VERSION 5.7 ;
  NOWIREEXTENSIONATPIN ON ;
  DIVIDERCHAR "/" ;
  BUSBITCHARS "[]" ;
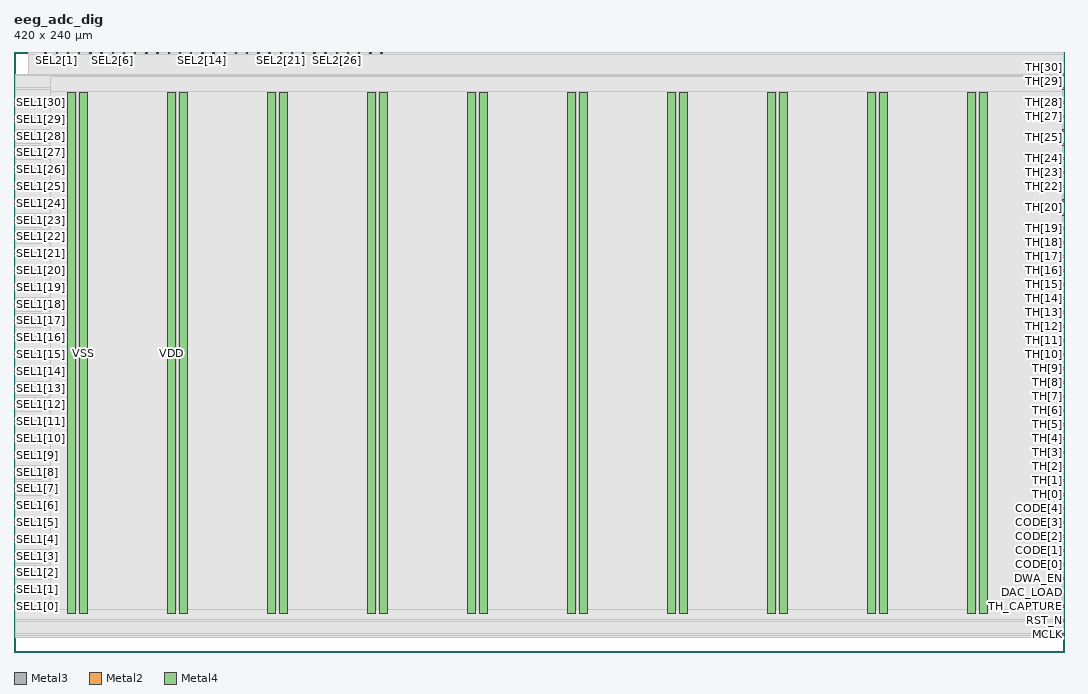
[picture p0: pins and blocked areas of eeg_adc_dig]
MACRO eeg_adc_dig
  CLASS BLOCK ;
  FOREIGN eeg_adc_dig ;
  ORIGIN 0.000 0.000 ;
  SIZE 420.000 BY 240.000 ;
  PIN CODE[0]
    DIRECTION OUTPUT ;
    USE SIGNAL ;
    ANTENNADIFFAREA 1.182800 ;
    PORT
      LAYER Metal3 ;
        RECT 419.440 34.720 420.000 35.280 ;
    END
  END CODE[0]
  PIN CODE[1]
    DIRECTION OUTPUT ;
    USE SIGNAL ;
    ANTENNADIFFAREA 1.182800 ;
    PORT
      LAYER Metal3 ;
        RECT 419.440 40.320 420.000 40.880 ;
    END
  END CODE[1]
  PIN CODE[2]
    DIRECTION OUTPUT ;
    USE SIGNAL ;
    ANTENNADIFFAREA 1.182800 ;
    PORT
      LAYER Metal3 ;
        RECT 419.440 45.920 420.000 46.480 ;
    END
  END CODE[2]
  PIN CODE[3]
    DIRECTION OUTPUT ;
    USE SIGNAL ;
    ANTENNADIFFAREA 1.182800 ;
    PORT
      LAYER Metal3 ;
        RECT 419.440 51.520 420.000 52.080 ;
    END
  END CODE[3]
  PIN CODE[4]
    DIRECTION OUTPUT ;
    USE SIGNAL ;
    ANTENNADIFFAREA 1.182800 ;
    PORT
      LAYER Metal3 ;
        RECT 419.440 57.120 420.000 57.680 ;
    END
  END CODE[4]
  PIN DAC_LOAD
    DIRECTION INPUT ;
    USE SIGNAL ;
    ANTENNAGATEAREA 1.102000 ;
    PORT
      LAYER Metal3 ;
        RECT 419.440 23.520 420.000 24.080 ;
    END
  END DAC_LOAD
  PIN DWA_EN
    DIRECTION INPUT ;
    USE SIGNAL ;
    ANTENNAGATEAREA 1.102000 ;
    PORT
      LAYER Metal3 ;
        RECT 419.440 29.120 420.000 29.680 ;
    END
  END DWA_EN
  PIN MCLK
    DIRECTION INPUT ;
    USE SIGNAL ;
    ANTENNAGATEAREA 4.738000 ;
    PORT
      LAYER Metal3 ;
        RECT 419.440 6.720 420.000 7.280 ;
    END
  END MCLK
  PIN RST_N
    DIRECTION INPUT ;
    USE SIGNAL ;
    ANTENNAGATEAREA 0.741000 ;
    PORT
      LAYER Metal3 ;
        RECT 419.440 12.320 420.000 12.880 ;
    END
  END RST_N
  PIN SEL1[0]
    DIRECTION OUTPUT ;
    USE SIGNAL ;
    ANTENNADIFFAREA 1.182800 ;
    PORT
      LAYER Metal3 ;
        RECT 0.000 17.920 0.560 18.480 ;
    END
  END SEL1[0]
  PIN SEL1[10]
    DIRECTION OUTPUT ;
    USE SIGNAL ;
    ANTENNADIFFAREA 1.182800 ;
    PORT
      LAYER Metal3 ;
        RECT 0.000 85.120 0.560 85.680 ;
    END
  END SEL1[10]
  PIN SEL1[11]
    DIRECTION OUTPUT ;
    USE SIGNAL ;
    ANTENNADIFFAREA 1.182800 ;
    PORT
      LAYER Metal3 ;
        RECT 0.000 91.840 0.560 92.400 ;
    END
  END SEL1[11]
  PIN SEL1[12]
    DIRECTION OUTPUT ;
    USE SIGNAL ;
    ANTENNADIFFAREA 1.182800 ;
    PORT
      LAYER Metal3 ;
        RECT 0.000 98.560 0.560 99.120 ;
    END
  END SEL1[12]
  PIN SEL1[13]
    DIRECTION OUTPUT ;
    USE SIGNAL ;
    ANTENNADIFFAREA 1.182800 ;
    PORT
      LAYER Metal3 ;
        RECT 0.000 105.280 0.560 105.840 ;
    END
  END SEL1[13]
  PIN SEL1[14]
    DIRECTION OUTPUT ;
    USE SIGNAL ;
    ANTENNADIFFAREA 1.182800 ;
    PORT
      LAYER Metal3 ;
        RECT 0.000 112.000 0.560 112.560 ;
    END
  END SEL1[14]
  PIN SEL1[15]
    DIRECTION OUTPUT ;
    USE SIGNAL ;
    ANTENNADIFFAREA 1.182800 ;
    PORT
      LAYER Metal3 ;
        RECT 0.000 118.720 0.560 119.280 ;
    END
  END SEL1[15]
  PIN SEL1[16]
    DIRECTION OUTPUT ;
    USE SIGNAL ;
    ANTENNADIFFAREA 1.182800 ;
    PORT
      LAYER Metal3 ;
        RECT 0.000 125.440 0.560 126.000 ;
    END
  END SEL1[16]
  PIN SEL1[17]
    DIRECTION OUTPUT ;
    USE SIGNAL ;
    ANTENNADIFFAREA 1.182800 ;
    PORT
      LAYER Metal3 ;
        RECT 0.000 132.160 0.560 132.720 ;
    END
  END SEL1[17]
  PIN SEL1[18]
    DIRECTION OUTPUT ;
    USE SIGNAL ;
    ANTENNADIFFAREA 1.182800 ;
    PORT
      LAYER Metal3 ;
        RECT 0.000 138.880 0.560 139.440 ;
    END
  END SEL1[18]
  PIN SEL1[19]
    DIRECTION OUTPUT ;
    USE SIGNAL ;
    ANTENNADIFFAREA 1.182800 ;
    PORT
      LAYER Metal3 ;
        RECT 0.000 145.600 0.560 146.160 ;
    END
  END SEL1[19]
  PIN SEL1[1]
    DIRECTION OUTPUT ;
    USE SIGNAL ;
    ANTENNADIFFAREA 1.182800 ;
    PORT
      LAYER Metal3 ;
        RECT 0.000 24.640 0.560 25.200 ;
    END
  END SEL1[1]
  PIN SEL1[20]
    DIRECTION OUTPUT ;
    USE SIGNAL ;
    ANTENNADIFFAREA 1.182800 ;
    PORT
      LAYER Metal3 ;
        RECT 0.000 152.320 0.560 152.880 ;
    END
  END SEL1[20]
  PIN SEL1[21]
    DIRECTION OUTPUT ;
    USE SIGNAL ;
    ANTENNADIFFAREA 1.182800 ;
    PORT
      LAYER Metal3 ;
        RECT 0.000 159.040 0.560 159.600 ;
    END
  END SEL1[21]
  PIN SEL1[22]
    DIRECTION OUTPUT ;
    USE SIGNAL ;
    ANTENNADIFFAREA 1.182800 ;
    PORT
      LAYER Metal3 ;
        RECT 0.000 165.760 0.560 166.320 ;
    END
  END SEL1[22]
  PIN SEL1[23]
    DIRECTION OUTPUT ;
    USE SIGNAL ;
    ANTENNADIFFAREA 1.182800 ;
    PORT
      LAYER Metal3 ;
        RECT 0.000 172.480 0.560 173.040 ;
    END
  END SEL1[23]
  PIN SEL1[24]
    DIRECTION OUTPUT ;
    USE SIGNAL ;
    ANTENNADIFFAREA 1.182800 ;
    PORT
      LAYER Metal3 ;
        RECT 0.000 179.200 0.560 179.760 ;
    END
  END SEL1[24]
  PIN SEL1[25]
    DIRECTION OUTPUT ;
    USE SIGNAL ;
    ANTENNADIFFAREA 1.182800 ;
    PORT
      LAYER Metal3 ;
        RECT 0.000 185.920 0.560 186.480 ;
    END
  END SEL1[25]
  PIN SEL1[26]
    DIRECTION OUTPUT ;
    USE SIGNAL ;
    ANTENNADIFFAREA 1.182800 ;
    PORT
      LAYER Metal3 ;
        RECT 0.000 192.640 0.560 193.200 ;
    END
  END SEL1[26]
  PIN SEL1[27]
    DIRECTION OUTPUT ;
    USE SIGNAL ;
    ANTENNADIFFAREA 1.182800 ;
    PORT
      LAYER Metal3 ;
        RECT 0.000 199.360 0.560 199.920 ;
    END
  END SEL1[27]
  PIN SEL1[28]
    DIRECTION OUTPUT ;
    USE SIGNAL ;
    ANTENNADIFFAREA 1.182800 ;
    PORT
      LAYER Metal3 ;
        RECT 0.000 206.080 0.560 206.640 ;
    END
  END SEL1[28]
  PIN SEL1[29]
    DIRECTION OUTPUT ;
    USE SIGNAL ;
    ANTENNADIFFAREA 1.182800 ;
    PORT
      LAYER Metal3 ;
        RECT 0.000 212.800 0.560 213.360 ;
    END
  END SEL1[29]
  PIN SEL1[2]
    DIRECTION OUTPUT ;
    USE SIGNAL ;
    ANTENNADIFFAREA 1.182800 ;
    PORT
      LAYER Metal3 ;
        RECT 0.000 31.360 0.560 31.920 ;
    END
  END SEL1[2]
  PIN SEL1[30]
    DIRECTION OUTPUT ;
    USE SIGNAL ;
    ANTENNADIFFAREA 1.182800 ;
    PORT
      LAYER Metal3 ;
        RECT 0.000 219.520 0.560 220.080 ;
    END
  END SEL1[30]
  PIN SEL1[3]
    DIRECTION OUTPUT ;
    USE SIGNAL ;
    ANTENNADIFFAREA 1.182800 ;
    PORT
      LAYER Metal3 ;
        RECT 0.000 38.080 0.560 38.640 ;
    END
  END SEL1[3]
  PIN SEL1[4]
    DIRECTION OUTPUT ;
    USE SIGNAL ;
    ANTENNADIFFAREA 1.182800 ;
    PORT
      LAYER Metal3 ;
        RECT 0.000 44.800 0.560 45.360 ;
    END
  END SEL1[4]
  PIN SEL1[5]
    DIRECTION OUTPUT ;
    USE SIGNAL ;
    ANTENNADIFFAREA 1.182800 ;
    PORT
      LAYER Metal3 ;
        RECT 0.000 51.520 0.560 52.080 ;
    END
  END SEL1[5]
  PIN SEL1[6]
    DIRECTION OUTPUT ;
    USE SIGNAL ;
    ANTENNADIFFAREA 1.182800 ;
    PORT
      LAYER Metal3 ;
        RECT 0.000 58.240 0.560 58.800 ;
    END
  END SEL1[6]
  PIN SEL1[7]
    DIRECTION OUTPUT ;
    USE SIGNAL ;
    ANTENNADIFFAREA 1.182800 ;
    PORT
      LAYER Metal3 ;
        RECT 0.000 64.960 0.560 65.520 ;
    END
  END SEL1[7]
  PIN SEL1[8]
    DIRECTION OUTPUT ;
    USE SIGNAL ;
    ANTENNADIFFAREA 1.182800 ;
    PORT
      LAYER Metal3 ;
        RECT 0.000 71.680 0.560 72.240 ;
    END
  END SEL1[8]
  PIN SEL1[9]
    DIRECTION OUTPUT ;
    USE SIGNAL ;
    ANTENNADIFFAREA 1.182800 ;
    PORT
      LAYER Metal3 ;
        RECT 0.000 78.400 0.560 78.960 ;
    END
  END SEL1[9]
  PIN SEL2[0]
    DIRECTION OUTPUT ;
    USE SIGNAL ;
    ANTENNADIFFAREA 1.182800 ;
    PORT
      LAYER Metal2 ;
        RECT 12.320 239.440 12.880 240.000 ;
    END
  END SEL2[0]
  PIN SEL2[10]
    DIRECTION OUTPUT ;
    USE SIGNAL ;
    ANTENNADIFFAREA 1.182800 ;
    PORT
      LAYER Metal2 ;
        RECT 57.120 239.440 57.680 240.000 ;
    END
  END SEL2[10]
  PIN SEL2[11]
    DIRECTION OUTPUT ;
    USE SIGNAL ;
    ANTENNADIFFAREA 1.182800 ;
    PORT
      LAYER Metal2 ;
        RECT 61.600 239.440 62.160 240.000 ;
    END
  END SEL2[11]
  PIN SEL2[12]
    DIRECTION OUTPUT ;
    USE SIGNAL ;
    ANTENNADIFFAREA 1.182800 ;
    PORT
      LAYER Metal2 ;
        RECT 66.080 239.440 66.640 240.000 ;
    END
  END SEL2[12]
  PIN SEL2[13]
    DIRECTION OUTPUT ;
    USE SIGNAL ;
    ANTENNADIFFAREA 1.182800 ;
    PORT
      LAYER Metal2 ;
        RECT 70.560 239.440 71.120 240.000 ;
    END
  END SEL2[13]
  PIN SEL2[14]
    DIRECTION OUTPUT ;
    USE SIGNAL ;
    ANTENNADIFFAREA 1.182800 ;
    PORT
      LAYER Metal2 ;
        RECT 75.040 239.440 75.600 240.000 ;
    END
  END SEL2[14]
  PIN SEL2[15]
    DIRECTION OUTPUT ;
    USE SIGNAL ;
    ANTENNADIFFAREA 1.182800 ;
    PORT
      LAYER Metal2 ;
        RECT 79.520 239.440 80.080 240.000 ;
    END
  END SEL2[15]
  PIN SEL2[16]
    DIRECTION OUTPUT ;
    USE SIGNAL ;
    ANTENNADIFFAREA 1.182800 ;
    PORT
      LAYER Metal2 ;
        RECT 84.000 239.440 84.560 240.000 ;
    END
  END SEL2[16]
  PIN SEL2[17]
    DIRECTION OUTPUT ;
    USE SIGNAL ;
    ANTENNADIFFAREA 1.182800 ;
    PORT
      LAYER Metal2 ;
        RECT 88.480 239.440 89.040 240.000 ;
    END
  END SEL2[17]
  PIN SEL2[18]
    DIRECTION OUTPUT ;
    USE SIGNAL ;
    ANTENNADIFFAREA 1.182800 ;
    PORT
      LAYER Metal2 ;
        RECT 92.960 239.440 93.520 240.000 ;
    END
  END SEL2[18]
  PIN SEL2[19]
    DIRECTION OUTPUT ;
    USE SIGNAL ;
    ANTENNADIFFAREA 1.182800 ;
    PORT
      LAYER Metal2 ;
        RECT 97.440 239.440 98.000 240.000 ;
    END
  END SEL2[19]
  PIN SEL2[1]
    DIRECTION OUTPUT ;
    USE SIGNAL ;
    ANTENNADIFFAREA 1.182800 ;
    PORT
      LAYER Metal2 ;
        RECT 16.800 239.440 17.360 240.000 ;
    END
  END SEL2[1]
  PIN SEL2[20]
    DIRECTION OUTPUT ;
    USE SIGNAL ;
    ANTENNADIFFAREA 1.182800 ;
    PORT
      LAYER Metal2 ;
        RECT 101.920 239.440 102.480 240.000 ;
    END
  END SEL2[20]
  PIN SEL2[21]
    DIRECTION OUTPUT ;
    USE SIGNAL ;
    ANTENNADIFFAREA 1.182800 ;
    PORT
      LAYER Metal2 ;
        RECT 106.400 239.440 106.960 240.000 ;
    END
  END SEL2[21]
  PIN SEL2[22]
    DIRECTION OUTPUT ;
    USE SIGNAL ;
    ANTENNADIFFAREA 1.182800 ;
    PORT
      LAYER Metal2 ;
        RECT 110.880 239.440 111.440 240.000 ;
    END
  END SEL2[22]
  PIN SEL2[23]
    DIRECTION OUTPUT ;
    USE SIGNAL ;
    ANTENNADIFFAREA 1.182800 ;
    PORT
      LAYER Metal2 ;
        RECT 115.360 239.440 115.920 240.000 ;
    END
  END SEL2[23]
  PIN SEL2[24]
    DIRECTION OUTPUT ;
    USE SIGNAL ;
    ANTENNADIFFAREA 1.182800 ;
    PORT
      LAYER Metal2 ;
        RECT 119.840 239.440 120.400 240.000 ;
    END
  END SEL2[24]
  PIN SEL2[25]
    DIRECTION OUTPUT ;
    USE SIGNAL ;
    ANTENNADIFFAREA 1.182800 ;
    PORT
      LAYER Metal2 ;
        RECT 124.320 239.440 124.880 240.000 ;
    END
  END SEL2[25]
  PIN SEL2[26]
    DIRECTION OUTPUT ;
    USE SIGNAL ;
    ANTENNADIFFAREA 1.182800 ;
    PORT
      LAYER Metal2 ;
        RECT 128.800 239.440 129.360 240.000 ;
    END
  END SEL2[26]
  PIN SEL2[27]
    DIRECTION OUTPUT ;
    USE SIGNAL ;
    ANTENNADIFFAREA 1.182800 ;
    PORT
      LAYER Metal2 ;
        RECT 133.280 239.440 133.840 240.000 ;
    END
  END SEL2[27]
  PIN SEL2[28]
    DIRECTION OUTPUT ;
    USE SIGNAL ;
    ANTENNADIFFAREA 1.182800 ;
    PORT
      LAYER Metal2 ;
        RECT 137.760 239.440 138.320 240.000 ;
    END
  END SEL2[28]
  PIN SEL2[29]
    DIRECTION OUTPUT ;
    USE SIGNAL ;
    ANTENNADIFFAREA 1.182800 ;
    PORT
      LAYER Metal2 ;
        RECT 142.240 239.440 142.800 240.000 ;
    END
  END SEL2[29]
  PIN SEL2[2]
    DIRECTION OUTPUT ;
    USE SIGNAL ;
    ANTENNADIFFAREA 1.182800 ;
    PORT
      LAYER Metal2 ;
        RECT 21.280 239.440 21.840 240.000 ;
    END
  END SEL2[2]
  PIN SEL2[30]
    DIRECTION OUTPUT ;
    USE SIGNAL ;
    ANTENNADIFFAREA 1.182800 ;
    PORT
      LAYER Metal2 ;
        RECT 146.720 239.440 147.280 240.000 ;
    END
  END SEL2[30]
  PIN SEL2[3]
    DIRECTION OUTPUT ;
    USE SIGNAL ;
    ANTENNADIFFAREA 1.182800 ;
    PORT
      LAYER Metal2 ;
        RECT 25.760 239.440 26.320 240.000 ;
    END
  END SEL2[3]
  PIN SEL2[4]
    DIRECTION OUTPUT ;
    USE SIGNAL ;
    ANTENNADIFFAREA 1.182800 ;
    PORT
      LAYER Metal2 ;
        RECT 30.240 239.440 30.800 240.000 ;
    END
  END SEL2[4]
  PIN SEL2[5]
    DIRECTION OUTPUT ;
    USE SIGNAL ;
    ANTENNADIFFAREA 1.182800 ;
    PORT
      LAYER Metal2 ;
        RECT 34.720 239.440 35.280 240.000 ;
    END
  END SEL2[5]
  PIN SEL2[6]
    DIRECTION OUTPUT ;
    USE SIGNAL ;
    ANTENNADIFFAREA 1.182800 ;
    PORT
      LAYER Metal2 ;
        RECT 39.200 239.440 39.760 240.000 ;
    END
  END SEL2[6]
  PIN SEL2[7]
    DIRECTION OUTPUT ;
    USE SIGNAL ;
    ANTENNADIFFAREA 1.182800 ;
    PORT
      LAYER Metal2 ;
        RECT 43.680 239.440 44.240 240.000 ;
    END
  END SEL2[7]
  PIN SEL2[8]
    DIRECTION OUTPUT ;
    USE SIGNAL ;
    ANTENNADIFFAREA 1.182800 ;
    PORT
      LAYER Metal2 ;
        RECT 48.160 239.440 48.720 240.000 ;
    END
  END SEL2[8]
  PIN SEL2[9]
    DIRECTION OUTPUT ;
    USE SIGNAL ;
    ANTENNADIFFAREA 1.182800 ;
    PORT
      LAYER Metal2 ;
        RECT 52.640 239.440 53.200 240.000 ;
    END
  END SEL2[9]
  PIN TH[0]
    DIRECTION INPUT ;
    USE SIGNAL ;
    ANTENNAGATEAREA 1.102000 ;
    PORT
      LAYER Metal3 ;
        RECT 419.440 62.720 420.000 63.280 ;
    END
  END TH[0]
  PIN TH[10]
    DIRECTION INPUT ;
    USE SIGNAL ;
    ANTENNAGATEAREA 1.102000 ;
    PORT
      LAYER Metal3 ;
        RECT 419.440 118.720 420.000 119.280 ;
    END
  END TH[10]
  PIN TH[11]
    DIRECTION INPUT ;
    USE SIGNAL ;
    ANTENNAGATEAREA 1.102000 ;
    PORT
      LAYER Metal3 ;
        RECT 419.440 124.320 420.000 124.880 ;
    END
  END TH[11]
  PIN TH[12]
    DIRECTION INPUT ;
    USE SIGNAL ;
    ANTENNAGATEAREA 1.102000 ;
    PORT
      LAYER Metal3 ;
        RECT 419.440 129.920 420.000 130.480 ;
    END
  END TH[12]
  PIN TH[13]
    DIRECTION INPUT ;
    USE SIGNAL ;
    ANTENNAGATEAREA 1.102000 ;
    PORT
      LAYER Metal3 ;
        RECT 419.440 135.520 420.000 136.080 ;
    END
  END TH[13]
  PIN TH[14]
    DIRECTION INPUT ;
    USE SIGNAL ;
    ANTENNAGATEAREA 1.102000 ;
    PORT
      LAYER Metal3 ;
        RECT 419.440 141.120 420.000 141.680 ;
    END
  END TH[14]
  PIN TH[15]
    DIRECTION INPUT ;
    USE SIGNAL ;
    ANTENNAGATEAREA 0.498500 ;
    PORT
      LAYER Metal3 ;
        RECT 419.440 146.720 420.000 147.280 ;
    END
  END TH[15]
  PIN TH[16]
    DIRECTION INPUT ;
    USE SIGNAL ;
    ANTENNAGATEAREA 1.102000 ;
    PORT
      LAYER Metal3 ;
        RECT 419.440 152.320 420.000 152.880 ;
    END
  END TH[16]
  PIN TH[17]
    DIRECTION INPUT ;
    USE SIGNAL ;
    ANTENNAGATEAREA 1.102000 ;
    PORT
      LAYER Metal3 ;
        RECT 419.440 157.920 420.000 158.480 ;
    END
  END TH[17]
  PIN TH[18]
    DIRECTION INPUT ;
    USE SIGNAL ;
    ANTENNAGATEAREA 1.102000 ;
    PORT
      LAYER Metal3 ;
        RECT 419.440 163.520 420.000 164.080 ;
    END
  END TH[18]
  PIN TH[19]
    DIRECTION INPUT ;
    USE SIGNAL ;
    ANTENNAGATEAREA 0.498500 ;
    PORT
      LAYER Metal3 ;
        RECT 419.440 169.120 420.000 169.680 ;
    END
  END TH[19]
  PIN TH[1]
    DIRECTION INPUT ;
    USE SIGNAL ;
    ANTENNAGATEAREA 1.102000 ;
    PORT
      LAYER Metal3 ;
        RECT 419.440 68.320 420.000 68.880 ;
    END
  END TH[1]
  PIN TH[20]
    DIRECTION INPUT ;
    USE SIGNAL ;
    ANTENNAGATEAREA 1.102000 ;
    PORT
      LAYER Metal3 ;
        RECT 419.440 174.720 420.000 175.280 ;
    END
  END TH[20]
  PIN TH[21]
    DIRECTION INPUT ;
    USE SIGNAL ;
    ANTENNAGATEAREA 1.102000 ;
    PORT
      LAYER Metal3 ;
        RECT 419.440 180.320 420.000 180.880 ;
    END
  END TH[21]
  PIN TH[22]
    DIRECTION INPUT ;
    USE SIGNAL ;
    ANTENNAGATEAREA 1.102000 ;
    PORT
      LAYER Metal3 ;
        RECT 419.440 185.920 420.000 186.480 ;
    END
  END TH[22]
  PIN TH[23]
    DIRECTION INPUT ;
    USE SIGNAL ;
    ANTENNAGATEAREA 0.498500 ;
    PORT
      LAYER Metal3 ;
        RECT 419.440 191.520 420.000 192.080 ;
    END
  END TH[23]
  PIN TH[24]
    DIRECTION INPUT ;
    USE SIGNAL ;
    ANTENNAGATEAREA 1.102000 ;
    PORT
      LAYER Metal3 ;
        RECT 419.440 197.120 420.000 197.680 ;
    END
  END TH[24]
  PIN TH[25]
    DIRECTION INPUT ;
    USE SIGNAL ;
    ANTENNAGATEAREA 1.102000 ;
    PORT
      LAYER Metal3 ;
        RECT 419.440 202.720 420.000 203.280 ;
    END
  END TH[25]
  PIN TH[26]
    DIRECTION INPUT ;
    USE SIGNAL ;
    ANTENNAGATEAREA 0.498500 ;
    PORT
      LAYER Metal3 ;
        RECT 419.440 208.320 420.000 208.880 ;
    END
  END TH[26]
  PIN TH[27]
    DIRECTION INPUT ;
    USE SIGNAL ;
    ANTENNAGATEAREA 0.498500 ;
    PORT
      LAYER Metal3 ;
        RECT 419.440 213.920 420.000 214.480 ;
    END
  END TH[27]
  PIN TH[28]
    DIRECTION INPUT ;
    USE SIGNAL ;
    ANTENNAGATEAREA 0.498500 ;
    PORT
      LAYER Metal3 ;
        RECT 419.440 219.520 420.000 220.080 ;
    END
  END TH[28]
  PIN TH[29]
    DIRECTION INPUT ;
    USE SIGNAL ;
    ANTENNAGATEAREA 1.102000 ;
    PORT
      LAYER Metal3 ;
        RECT 419.440 225.120 420.000 225.680 ;
    END
  END TH[29]
  PIN TH[2]
    DIRECTION INPUT ;
    USE SIGNAL ;
    ANTENNAGATEAREA 0.498500 ;
    PORT
      LAYER Metal3 ;
        RECT 419.440 73.920 420.000 74.480 ;
    END
  END TH[2]
  PIN TH[30]
    DIRECTION INPUT ;
    USE SIGNAL ;
    ANTENNAGATEAREA 1.102000 ;
    PORT
      LAYER Metal3 ;
        RECT 419.440 230.720 420.000 231.280 ;
    END
  END TH[30]
  PIN TH[3]
    DIRECTION INPUT ;
    USE SIGNAL ;
    ANTENNAGATEAREA 1.102000 ;
    PORT
      LAYER Metal3 ;
        RECT 419.440 79.520 420.000 80.080 ;
    END
  END TH[3]
  PIN TH[4]
    DIRECTION INPUT ;
    USE SIGNAL ;
    ANTENNAGATEAREA 1.102000 ;
    PORT
      LAYER Metal3 ;
        RECT 419.440 85.120 420.000 85.680 ;
    END
  END TH[4]
  PIN TH[5]
    DIRECTION INPUT ;
    USE SIGNAL ;
    ANTENNAGATEAREA 0.498500 ;
    PORT
      LAYER Metal3 ;
        RECT 419.440 90.720 420.000 91.280 ;
    END
  END TH[5]
  PIN TH[6]
    DIRECTION INPUT ;
    USE SIGNAL ;
    ANTENNAGATEAREA 0.498500 ;
    PORT
      LAYER Metal3 ;
        RECT 419.440 96.320 420.000 96.880 ;
    END
  END TH[6]
  PIN TH[7]
    DIRECTION INPUT ;
    USE SIGNAL ;
    ANTENNAGATEAREA 1.102000 ;
    PORT
      LAYER Metal3 ;
        RECT 419.440 101.920 420.000 102.480 ;
    END
  END TH[7]
  PIN TH[8]
    DIRECTION INPUT ;
    USE SIGNAL ;
    ANTENNAGATEAREA 1.102000 ;
    PORT
      LAYER Metal3 ;
        RECT 419.440 107.520 420.000 108.080 ;
    END
  END TH[8]
  PIN TH[9]
    DIRECTION INPUT ;
    USE SIGNAL ;
    ANTENNAGATEAREA 1.102000 ;
    PORT
      LAYER Metal3 ;
        RECT 419.440 113.120 420.000 113.680 ;
    END
  END TH[9]
  PIN TH_CAPTURE
    DIRECTION INPUT ;
    USE SIGNAL ;
    ANTENNAGATEAREA 0.498500 ;
    PORT
      LAYER Metal3 ;
        RECT 419.440 17.920 420.000 18.480 ;
    END
  END TH_CAPTURE
  PIN VDD
    DIRECTION INOUT ;
    USE POWER ;
    PORT
      LAYER Metal4 ;
        RECT 21.540 15.380 24.540 223.740 ;
    END
    PORT
      LAYER Metal4 ;
        RECT 61.540 15.380 64.540 223.740 ;
    END
    PORT
      LAYER Metal4 ;
        RECT 101.540 15.380 104.540 223.740 ;
    END
    PORT
      LAYER Metal4 ;
        RECT 141.540 15.380 144.540 223.740 ;
    END
    PORT
      LAYER Metal4 ;
        RECT 181.540 15.380 184.540 223.740 ;
    END
    PORT
      LAYER Metal4 ;
        RECT 221.540 15.380 224.540 223.740 ;
    END
    PORT
      LAYER Metal4 ;
        RECT 261.540 15.380 264.540 223.740 ;
    END
    PORT
      LAYER Metal4 ;
        RECT 301.540 15.380 304.540 223.740 ;
    END
    PORT
      LAYER Metal4 ;
        RECT 341.540 15.380 344.540 223.740 ;
    END
    PORT
      LAYER Metal4 ;
        RECT 381.540 15.380 384.540 223.740 ;
    END
  END VDD
  PIN VSS
    DIRECTION INOUT ;
    USE GROUND ;
    PORT
      LAYER Metal4 ;
        RECT 26.240 15.380 29.240 223.740 ;
    END
    PORT
      LAYER Metal4 ;
        RECT 66.240 15.380 69.240 223.740 ;
    END
    PORT
      LAYER Metal4 ;
        RECT 106.240 15.380 109.240 223.740 ;
    END
    PORT
      LAYER Metal4 ;
        RECT 146.240 15.380 149.240 223.740 ;
    END
    PORT
      LAYER Metal4 ;
        RECT 186.240 15.380 189.240 223.740 ;
    END
    PORT
      LAYER Metal4 ;
        RECT 226.240 15.380 229.240 223.740 ;
    END
    PORT
      LAYER Metal4 ;
        RECT 266.240 15.380 269.240 223.740 ;
    END
    PORT
      LAYER Metal4 ;
        RECT 306.240 15.380 309.240 223.740 ;
    END
    PORT
      LAYER Metal4 ;
        RECT 346.240 15.380 349.240 223.740 ;
    END
    PORT
      LAYER Metal4 ;
        RECT 386.240 15.380 389.240 223.740 ;
    END
  END VSS
  OBS
      LAYER Nwell ;
        RECT 6.290 15.250 413.710 223.870 ;
      LAYER Metal1 ;
        RECT 6.720 15.380 413.280 223.740 ;
      LAYER Metal2 ;
        RECT 5.740 239.140 12.020 239.860 ;
        RECT 13.180 239.140 16.500 239.860 ;
        RECT 17.660 239.140 20.980 239.860 ;
        RECT 22.140 239.140 25.460 239.860 ;
        RECT 26.620 239.140 29.940 239.860 ;
        RECT 31.100 239.140 34.420 239.860 ;
        RECT 35.580 239.140 38.900 239.860 ;
        RECT 40.060 239.140 43.380 239.860 ;
        RECT 44.540 239.140 47.860 239.860 ;
        RECT 49.020 239.140 52.340 239.860 ;
        RECT 53.500 239.140 56.820 239.860 ;
        RECT 57.980 239.140 61.300 239.860 ;
        RECT 62.460 239.140 65.780 239.860 ;
        RECT 66.940 239.140 70.260 239.860 ;
        RECT 71.420 239.140 74.740 239.860 ;
        RECT 75.900 239.140 79.220 239.860 ;
        RECT 80.380 239.140 83.700 239.860 ;
        RECT 84.860 239.140 88.180 239.860 ;
        RECT 89.340 239.140 92.660 239.860 ;
        RECT 93.820 239.140 97.140 239.860 ;
        RECT 98.300 239.140 101.620 239.860 ;
        RECT 102.780 239.140 106.100 239.860 ;
        RECT 107.260 239.140 110.580 239.860 ;
        RECT 111.740 239.140 115.060 239.860 ;
        RECT 116.220 239.140 119.540 239.860 ;
        RECT 120.700 239.140 124.020 239.860 ;
        RECT 125.180 239.140 128.500 239.860 ;
        RECT 129.660 239.140 132.980 239.860 ;
        RECT 134.140 239.140 137.460 239.860 ;
        RECT 138.620 239.140 141.940 239.860 ;
        RECT 143.100 239.140 146.420 239.860 ;
        RECT 147.580 239.140 419.860 239.860 ;
        RECT 5.740 5.690 419.860 239.140 ;
      LAYER Metal3 ;
        RECT 0.560 230.420 419.140 231.140 ;
        RECT 0.560 225.980 419.860 230.420 ;
        RECT 0.560 224.820 419.140 225.980 ;
        RECT 0.560 220.380 419.860 224.820 ;
        RECT 0.860 219.220 419.140 220.380 ;
        RECT 0.560 214.780 419.860 219.220 ;
        RECT 0.560 213.660 419.140 214.780 ;
        RECT 0.860 213.620 419.140 213.660 ;
        RECT 0.860 212.500 419.860 213.620 ;
        RECT 0.560 209.180 419.860 212.500 ;
        RECT 0.560 208.020 419.140 209.180 ;
        RECT 0.560 206.940 419.860 208.020 ;
        RECT 0.860 205.780 419.860 206.940 ;
        RECT 0.560 203.580 419.860 205.780 ;
        RECT 0.560 202.420 419.140 203.580 ;
        RECT 0.560 200.220 419.860 202.420 ;
        RECT 0.860 199.060 419.860 200.220 ;
        RECT 0.560 197.980 419.860 199.060 ;
        RECT 0.560 196.820 419.140 197.980 ;
        RECT 0.560 193.500 419.860 196.820 ;
        RECT 0.860 192.380 419.860 193.500 ;
        RECT 0.860 192.340 419.140 192.380 ;
        RECT 0.560 191.220 419.140 192.340 ;
        RECT 0.560 186.780 419.860 191.220 ;
        RECT 0.860 185.620 419.140 186.780 ;
        RECT 0.560 181.180 419.860 185.620 ;
        RECT 0.560 180.060 419.140 181.180 ;
        RECT 0.860 180.020 419.140 180.060 ;
        RECT 0.860 178.900 419.860 180.020 ;
        RECT 0.560 175.580 419.860 178.900 ;
        RECT 0.560 174.420 419.140 175.580 ;
        RECT 0.560 173.340 419.860 174.420 ;
        RECT 0.860 172.180 419.860 173.340 ;
        RECT 0.560 169.980 419.860 172.180 ;
        RECT 0.560 168.820 419.140 169.980 ;
        RECT 0.560 166.620 419.860 168.820 ;
        RECT 0.860 165.460 419.860 166.620 ;
        RECT 0.560 164.380 419.860 165.460 ;
        RECT 0.560 163.220 419.140 164.380 ;
        RECT 0.560 159.900 419.860 163.220 ;
        RECT 0.860 158.780 419.860 159.900 ;
        RECT 0.860 158.740 419.140 158.780 ;
        RECT 0.560 157.620 419.140 158.740 ;
        RECT 0.560 153.180 419.860 157.620 ;
        RECT 0.860 152.020 419.140 153.180 ;
        RECT 0.560 147.580 419.860 152.020 ;
        RECT 0.560 146.460 419.140 147.580 ;
        RECT 0.860 146.420 419.140 146.460 ;
        RECT 0.860 145.300 419.860 146.420 ;
        RECT 0.560 141.980 419.860 145.300 ;
        RECT 0.560 140.820 419.140 141.980 ;
        RECT 0.560 139.740 419.860 140.820 ;
        RECT 0.860 138.580 419.860 139.740 ;
        RECT 0.560 136.380 419.860 138.580 ;
        RECT 0.560 135.220 419.140 136.380 ;
        RECT 0.560 133.020 419.860 135.220 ;
        RECT 0.860 131.860 419.860 133.020 ;
        RECT 0.560 130.780 419.860 131.860 ;
        RECT 0.560 129.620 419.140 130.780 ;
        RECT 0.560 126.300 419.860 129.620 ;
        RECT 0.860 125.180 419.860 126.300 ;
        RECT 0.860 125.140 419.140 125.180 ;
        RECT 0.560 124.020 419.140 125.140 ;
        RECT 0.560 119.580 419.860 124.020 ;
        RECT 0.860 118.420 419.140 119.580 ;
        RECT 0.560 113.980 419.860 118.420 ;
        RECT 0.560 112.860 419.140 113.980 ;
        RECT 0.860 112.820 419.140 112.860 ;
        RECT 0.860 111.700 419.860 112.820 ;
        RECT 0.560 108.380 419.860 111.700 ;
        RECT 0.560 107.220 419.140 108.380 ;
        RECT 0.560 106.140 419.860 107.220 ;
        RECT 0.860 104.980 419.860 106.140 ;
        RECT 0.560 102.780 419.860 104.980 ;
        RECT 0.560 101.620 419.140 102.780 ;
        RECT 0.560 99.420 419.860 101.620 ;
        RECT 0.860 98.260 419.860 99.420 ;
        RECT 0.560 97.180 419.860 98.260 ;
        RECT 0.560 96.020 419.140 97.180 ;
        RECT 0.560 92.700 419.860 96.020 ;
        RECT 0.860 91.580 419.860 92.700 ;
        RECT 0.860 91.540 419.140 91.580 ;
        RECT 0.560 90.420 419.140 91.540 ;
        RECT 0.560 85.980 419.860 90.420 ;
        RECT 0.860 84.820 419.140 85.980 ;
        RECT 0.560 80.380 419.860 84.820 ;
        RECT 0.560 79.260 419.140 80.380 ;
        RECT 0.860 79.220 419.140 79.260 ;
        RECT 0.860 78.100 419.860 79.220 ;
        RECT 0.560 74.780 419.860 78.100 ;
        RECT 0.560 73.620 419.140 74.780 ;
        RECT 0.560 72.540 419.860 73.620 ;
        RECT 0.860 71.380 419.860 72.540 ;
        RECT 0.560 69.180 419.860 71.380 ;
        RECT 0.560 68.020 419.140 69.180 ;
        RECT 0.560 65.820 419.860 68.020 ;
        RECT 0.860 64.660 419.860 65.820 ;
        RECT 0.560 63.580 419.860 64.660 ;
        RECT 0.560 62.420 419.140 63.580 ;
        RECT 0.560 59.100 419.860 62.420 ;
        RECT 0.860 57.980 419.860 59.100 ;
        RECT 0.860 57.940 419.140 57.980 ;
        RECT 0.560 56.820 419.140 57.940 ;
        RECT 0.560 52.380 419.860 56.820 ;
        RECT 0.860 51.220 419.140 52.380 ;
        RECT 0.560 46.780 419.860 51.220 ;
        RECT 0.560 45.660 419.140 46.780 ;
        RECT 0.860 45.620 419.140 45.660 ;
        RECT 0.860 44.500 419.860 45.620 ;
        RECT 0.560 41.180 419.860 44.500 ;
        RECT 0.560 40.020 419.140 41.180 ;
        RECT 0.560 38.940 419.860 40.020 ;
        RECT 0.860 37.780 419.860 38.940 ;
        RECT 0.560 35.580 419.860 37.780 ;
        RECT 0.560 34.420 419.140 35.580 ;
        RECT 0.560 32.220 419.860 34.420 ;
        RECT 0.860 31.060 419.860 32.220 ;
        RECT 0.560 29.980 419.860 31.060 ;
        RECT 0.560 28.820 419.140 29.980 ;
        RECT 0.560 25.500 419.860 28.820 ;
        RECT 0.860 24.380 419.860 25.500 ;
        RECT 0.860 24.340 419.140 24.380 ;
        RECT 0.560 23.220 419.140 24.340 ;
        RECT 0.560 18.780 419.860 23.220 ;
        RECT 0.860 17.620 419.140 18.780 ;
        RECT 0.560 13.180 419.860 17.620 ;
        RECT 0.560 12.020 419.140 13.180 ;
        RECT 0.560 7.580 419.860 12.020 ;
        RECT 0.560 6.420 419.140 7.580 ;
        RECT 0.560 5.740 419.860 6.420 ;
      LAYER Metal4 ;
        RECT 14.700 224.040 419.300 230.070 ;
        RECT 14.700 16.890 21.240 224.040 ;
        RECT 24.840 16.890 25.940 224.040 ;
        RECT 29.540 16.890 61.240 224.040 ;
        RECT 64.840 16.890 65.940 224.040 ;
        RECT 69.540 16.890 101.240 224.040 ;
        RECT 104.840 16.890 105.940 224.040 ;
        RECT 109.540 16.890 141.240 224.040 ;
        RECT 144.840 16.890 145.940 224.040 ;
        RECT 149.540 16.890 181.240 224.040 ;
        RECT 184.840 16.890 185.940 224.040 ;
        RECT 189.540 16.890 221.240 224.040 ;
        RECT 224.840 16.890 225.940 224.040 ;
        RECT 229.540 16.890 261.240 224.040 ;
        RECT 264.840 16.890 265.940 224.040 ;
        RECT 269.540 16.890 301.240 224.040 ;
        RECT 304.840 16.890 305.940 224.040 ;
        RECT 309.540 16.890 341.240 224.040 ;
        RECT 344.840 16.890 345.940 224.040 ;
        RECT 349.540 16.890 381.240 224.040 ;
        RECT 384.840 16.890 385.940 224.040 ;
        RECT 389.540 16.890 419.300 224.040 ;
  END
END eeg_adc_dig
END LIBRARY

